VERSION 5.8 ;
BUSBITCHARS "[]" ;
DIVIDERCHAR "/" ;
UNITS
    DATABASE MICRONS 1000 ;
END UNITS

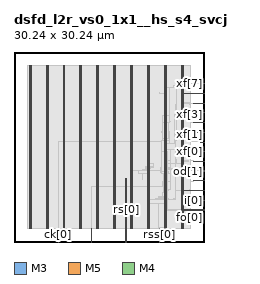
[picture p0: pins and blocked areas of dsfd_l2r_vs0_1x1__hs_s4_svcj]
MACRO dsfd_l2r_vs0_1x1__hs_s4_svcj
  FOREIGN dsfd_l2r_vs0_1x1__hs_s4_svcj 0 0 ;
  CLASS BLOCK ;
  SIZE 30.24 BY 30.24 ;
  PIN ck[0]
    DIRECTION INPUT ;
    USE SIGNAL ;
    PORT
      LAYER M3 ;
        RECT  7.02 0 7.038 0.144 ;
    END
    PORT
      LAYER M3 ;
        RECT  7.02 0.108 7.038 0.52 ;
    END
  END ck[0]
  PIN cks[0]
    DIRECTION INPUT ;
    USE SIGNAL ;
    PORT
      LAYER M5 ;
        RECT  12.384 0 12.408 0.192 ;
    END
    PORT
      LAYER M5 ;
        RECT  12.384 0.144 12.408 2.137 ;
    END
  END cks[0]
  PIN fo[0]
    DIRECTION OUTPUT ;
    USE SIGNAL ;
    PORT
      LAYER M4 ;
        RECT  30.048 5.088 30.24 5.112 ;
    END
    PORT
      LAYER M4 ;
        RECT  27.004 5.088 30.06 5.112 ;
    END
  END fo[0]
  PIN i[0]
    DIRECTION INPUT ;
    USE SIGNAL ;
    PORT
      LAYER M4 ;
        RECT  30.048 6.624 30.24 6.648 ;
    END
    PORT
      LAYER M4 ;
        RECT  28.501 6.624 30.06 6.648 ;
    END
  END i[0]
  PIN i[1]
    DIRECTION INPUT ;
    USE SIGNAL ;
    PORT
      LAYER M4 ;
        RECT  30.048 8.208 30.24 8.232 ;
    END
    PORT
      LAYER M4 ;
        RECT  27.004 8.208 30.06 8.232 ;
    END
  END i[1]
  PIN od[0]
    DIRECTION OUTPUT ;
    USE SIGNAL ;
    PORT
      LAYER M4 ;
        RECT  30.048 9.744 30.24 9.768 ;
    END
    PORT
      LAYER M4 ;
        RECT  28.501 9.744 30.06 9.768 ;
    END
  END od[0]
  PIN od[1]
    DIRECTION OUTPUT ;
    USE SIGNAL ;
    PORT
      LAYER M4 ;
        RECT  30.048 11.28 30.24 11.304 ;
    END
    PORT
      LAYER M4 ;
        RECT  29.653 11.28 30.06 11.304 ;
    END
  END od[1]
  PIN od[2]
    DIRECTION OUTPUT ;
    USE SIGNAL ;
    PORT
      LAYER M4 ;
        RECT  30.048 12.816 30.24 12.84 ;
    END
    PORT
      LAYER M4 ;
        RECT  28.501 12.816 30.06 12.84 ;
    END
  END od[2]
  PIN rs[0]
    DIRECTION INPUT ;
    USE SIGNAL ;
    PORT
      LAYER M3 ;
        RECT  17.82 0 17.838 0.144 ;
    END
    PORT
      LAYER M3 ;
        RECT  17.82 0.108 17.838 10.085 ;
    END
  END rs[0]
  PIN rss[0]
    DIRECTION INPUT ;
    USE SIGNAL ;
    PORT
      LAYER M5 ;
        RECT  23.184 0 23.208 0.192 ;
    END
    PORT
      LAYER M5 ;
        RECT  23.184 0.144 23.208 2.137 ;
    END
  END rss[0]
  PIN xf[0]
    DIRECTION INPUT ;
    USE SIGNAL ;
    PORT
      LAYER M4 ;
        RECT  30.048 14.352 30.24 14.376 ;
    END
    PORT
      LAYER M4 ;
        RECT  29.653 14.352 30.06 14.376 ;
    END
  END xf[0]
  PIN xf[1]
    DIRECTION INPUT ;
    USE SIGNAL ;
    PORT
      LAYER M4 ;
        RECT  30.048 15.888 30.24 15.912 ;
    END
    PORT
      LAYER M4 ;
        RECT  29.653 15.888 30.06 15.912 ;
    END
  END xf[1]
  PIN xf[2]
    DIRECTION INPUT ;
    USE SIGNAL ;
    PORT
      LAYER M4 ;
        RECT  30.048 17.424 30.24 17.448 ;
    END
    PORT
      LAYER M4 ;
        RECT  28.501 17.424 30.06 17.448 ;
    END
  END xf[2]
  PIN xf[3]
    DIRECTION INPUT ;
    USE SIGNAL ;
    PORT
      LAYER M4 ;
        RECT  30.048 19.008 30.24 19.032 ;
    END
    PORT
      LAYER M4 ;
        RECT  28.501 19.008 30.06 19.032 ;
    END
  END xf[3]
  PIN xf[4]
    DIRECTION INPUT ;
    USE SIGNAL ;
    PORT
      LAYER M4 ;
        RECT  30.048 20.544 30.24 20.568 ;
    END
    PORT
      LAYER M4 ;
        RECT  28.501 20.544 30.06 20.568 ;
    END
  END xf[4]
  PIN xf[5]
    DIRECTION INPUT ;
    USE SIGNAL ;
    PORT
      LAYER M4 ;
        RECT  30.048 22.08 30.24 22.104 ;
    END
    PORT
      LAYER M4 ;
        RECT  28.501 22.08 30.06 22.104 ;
    END
  END xf[5]
  PIN xf[6]
    DIRECTION INPUT ;
    USE SIGNAL ;
    PORT
      LAYER M4 ;
        RECT  30.048 23.616 30.24 23.64 ;
    END
    PORT
      LAYER M4 ;
        RECT  27.004 23.616 30.06 23.64 ;
    END
  END xf[6]
  PIN xf[7]
    DIRECTION INPUT ;
    USE SIGNAL ;
    PORT
      LAYER M4 ;
        RECT  30.048 25.152 30.24 25.176 ;
    END
    PORT
      LAYER M4 ;
        RECT  29.653 25.152 30.06 25.176 ;
    END
  END xf[7]
  PIN VDD
    DIRECTION INOUT ;
    USE POWER ;
    PORT
      LAYER M5 ;
        RECT  26.892 2.151 27.012 28.089 ;
        RECT  24.192 2.151 24.312 28.089 ;
        RECT  21.492 2.151 21.612 28.089 ;
        RECT  18.792 2.151 18.912 28.089 ;
        RECT  16.092 2.151 16.212 28.089 ;
        RECT  13.392 2.151 13.512 28.089 ;
        RECT  10.692 2.151 10.812 28.089 ;
        RECT  7.992 2.151 8.112 28.089 ;
        RECT  5.292 2.151 5.412 28.089 ;
        RECT  2.592 2.151 2.712 28.089 ;
    END
  END VDD
  PIN VSS
    DIRECTION INOUT ;
    USE GROUND ;
    PORT
      LAYER M5 ;
        RECT  26.7 2.137 26.82 28.103 ;
        RECT  24 2.137 24.12 28.103 ;
        RECT  21.3 2.137 21.42 28.103 ;
        RECT  18.6 2.137 18.72 28.103 ;
        RECT  15.9 2.137 16.02 28.103 ;
        RECT  13.2 2.137 13.32 28.103 ;
        RECT  10.5 2.137 10.62 28.103 ;
        RECT  7.8 2.137 7.92 28.103 ;
        RECT  5.1 2.137 5.22 28.103 ;
        RECT  2.4 2.137 2.52 28.103 ;
    END
  END VSS
  # OT_OBS_CLOSED layer=M5 d_um=1.536 added=0
  OBS
    LAYER RVTN ;
     RECT  2.16 2.16 28.08 2.295 ;
     RECT  2.16 2.565 28.08 2.835 ;
     RECT  2.16 3.105 28.08 3.375 ;
     RECT  2.16 3.645 28.08 3.915 ;
     RECT  2.16 4.185 28.08 4.455 ;
     RECT  2.16 4.725 28.08 4.995 ;
     RECT  2.16 5.265 28.08 5.535 ;
     RECT  2.16 5.805 28.08 6.075 ;
     RECT  2.16 6.345 28.08 6.615 ;
     RECT  2.16 6.885 28.08 7.155 ;
     RECT  2.16 7.425 28.08 7.695 ;
     RECT  2.16 7.965 28.08 8.235 ;
     RECT  2.16 8.505 28.08 8.775 ;
     RECT  2.16 9.045 28.08 9.315 ;
     RECT  2.16 9.585 28.08 9.855 ;
     RECT  2.16 10.125 28.08 10.395 ;
     RECT  2.16 10.665 28.08 10.935 ;
     RECT  2.16 11.205 28.08 11.475 ;
     RECT  2.16 11.745 28.08 12.015 ;
     RECT  2.16 12.285 28.08 12.555 ;
     RECT  2.16 12.825 28.08 13.095 ;
     RECT  2.16 13.365 28.08 13.635 ;
     RECT  2.16 13.905 28.08 14.175 ;
     RECT  2.16 14.445 28.08 14.715 ;
     RECT  2.16 14.985 28.08 15.255 ;
     RECT  2.16 15.525 28.08 15.795 ;
     RECT  2.16 16.065 28.08 16.335 ;
     RECT  2.16 16.605 28.08 16.875 ;
     RECT  2.16 17.145 28.08 17.415 ;
     RECT  2.16 17.685 28.08 17.955 ;
     RECT  2.16 18.225 28.08 18.495 ;
     RECT  2.16 18.765 28.08 19.035 ;
     RECT  2.16 19.305 28.08 19.575 ;
     RECT  2.16 19.845 28.08 20.115 ;
     RECT  2.16 20.385 28.08 20.655 ;
     RECT  2.16 20.925 28.08 21.195 ;
     RECT  2.16 21.465 28.08 21.735 ;
     RECT  2.16 22.005 28.08 22.275 ;
     RECT  2.16 22.545 28.08 22.815 ;
     RECT  2.16 23.085 28.08 23.355 ;
     RECT  2.16 23.625 28.08 23.895 ;
     RECT  2.16 24.165 28.08 24.435 ;
     RECT  2.16 24.705 28.08 24.975 ;
     RECT  2.16 25.245 28.08 25.515 ;
     RECT  2.16 25.785 28.08 26.055 ;
     RECT  2.16 26.325 28.08 26.595 ;
     RECT  2.16 26.865 28.08 27.135 ;
     RECT  2.16 27.405 28.08 27.675 ;
     RECT  2.16 27.945 28.08 28.08 ;
    LAYER RVTP ;
     RECT  2.16 2.295 28.08 2.565 ;
     RECT  2.16 2.835 28.08 3.105 ;
     RECT  2.16 3.375 28.08 3.645 ;
     RECT  2.16 3.915 28.08 4.185 ;
     RECT  2.16 4.455 28.08 4.725 ;
     RECT  2.16 4.995 28.08 5.265 ;
     RECT  2.16 5.535 28.08 5.805 ;
     RECT  2.16 6.075 28.08 6.345 ;
     RECT  2.16 6.615 28.08 6.885 ;
     RECT  2.16 7.155 28.08 7.425 ;
     RECT  2.16 7.695 28.08 7.965 ;
     RECT  2.16 8.235 28.08 8.505 ;
     RECT  2.16 8.775 28.08 9.045 ;
     RECT  2.16 9.315 28.08 9.585 ;
     RECT  2.16 9.855 28.08 10.125 ;
     RECT  2.16 10.395 28.08 10.665 ;
     RECT  2.16 10.935 28.08 11.205 ;
     RECT  2.16 11.475 28.08 11.745 ;
     RECT  2.16 12.015 28.08 12.285 ;
     RECT  2.16 12.555 28.08 12.825 ;
     RECT  2.16 13.095 28.08 13.365 ;
     RECT  2.16 13.635 28.08 13.905 ;
     RECT  2.16 14.175 28.08 14.445 ;
     RECT  2.16 14.715 28.08 14.985 ;
     RECT  2.16 15.255 28.08 15.525 ;
     RECT  2.16 15.795 28.08 16.065 ;
     RECT  2.16 16.335 28.08 16.605 ;
     RECT  2.16 16.875 28.08 17.145 ;
     RECT  2.16 17.415 28.08 17.685 ;
     RECT  2.16 17.955 28.08 18.225 ;
     RECT  2.16 18.495 28.08 18.765 ;
     RECT  2.16 19.035 28.08 19.305 ;
     RECT  2.16 19.575 28.08 19.845 ;
     RECT  2.16 20.115 28.08 20.385 ;
     RECT  2.16 20.655 28.08 20.925 ;
     RECT  2.16 21.195 28.08 21.465 ;
     RECT  2.16 21.735 28.08 22.005 ;
     RECT  2.16 22.275 28.08 22.545 ;
     RECT  2.16 22.815 28.08 23.085 ;
     RECT  2.16 23.355 28.08 23.625 ;
     RECT  2.16 23.895 28.08 24.165 ;
     RECT  2.16 24.435 28.08 24.705 ;
     RECT  2.16 24.975 28.08 25.245 ;
     RECT  2.16 25.515 28.08 25.785 ;
     RECT  2.16 26.055 28.08 26.325 ;
     RECT  2.16 26.595 28.08 26.865 ;
     RECT  2.16 27.135 28.08 27.405 ;
     RECT  2.16 27.675 28.08 27.945 ;
    LAYER M1 ;
     RECT  2.16 2.151 28.08 28.089 ;
    LAYER M2 ;
     RECT  6.943 0.531 7.043 0.549 ;
     RECT  2.16 2.151 28.08 28.089 ;
     RECT  28.08 6.696 28.535 6.714 ;
     RECT  28.08 9.666 28.535 9.684 ;
     RECT  28.08 12.906 28.535 12.924 ;
     RECT  28.08 17.622 28.535 17.64 ;
     RECT  28.08 18.972 28.535 18.99 ;
     RECT  28.08 20.628 28.535 20.646 ;
     RECT  28.08 22.086 28.535 22.104 ;
     RECT  28.08 11.376 29.687 11.394 ;
     RECT  28.08 14.382 29.687 14.4 ;
     RECT  28.08 16.002 29.687 16.02 ;
     RECT  28.08 25.254 29.687 25.272 ;
    LAYER M3 ;
     RECT  6.948 0.52 7.038 0.554 ;
     RECT  6.948 0.554 6.966 0.557 ;
     RECT  2.415 2.143 2.505 2.413 ;
     RECT  5.115 2.143 5.205 2.413 ;
     RECT  7.815 2.143 7.905 2.413 ;
     RECT  10.515 2.143 10.605 2.413 ;
     RECT  13.215 2.143 13.305 2.413 ;
     RECT  15.915 2.143 16.005 2.413 ;
     RECT  18.615 2.143 18.705 2.413 ;
     RECT  21.315 2.143 21.405 2.413 ;
     RECT  24.015 2.143 24.105 2.413 ;
     RECT  26.715 2.143 26.805 2.413 ;
     RECT  26.715 2.413 26.997 4.891 ;
     RECT  23.04 2.251 23.058 4.955 ;
     RECT  26.715 4.891 27.09 5.035 ;
     RECT  26.064 5.035 27.09 5.117 ;
     RECT  21.315 2.413 21.597 6.115 ;
     RECT  23.004 5.071 23.022 6.115 ;
     RECT  21.315 6.115 23.022 6.151 ;
     RECT  24.015 2.413 24.297 6.151 ;
     RECT  26.715 5.117 26.997 6.691 ;
     RECT  28.512 6.619 28.53 6.719 ;
     RECT  25.704 6.781 25.722 6.808 ;
     RECT  21.315 6.151 24.297 6.809 ;
     RECT  22.464 6.809 24.297 6.845 ;
     RECT  25.416 6.808 25.722 6.845 ;
     RECT  26.715 6.691 27.378 6.845 ;
     RECT  22.932 6.845 24.297 7.079 ;
     RECT  23.076 7.079 24.297 7.223 ;
     RECT  23.688 7.223 24.297 7.889 ;
     RECT  25.704 6.845 25.722 8.131 ;
     RECT  26.715 6.845 26.997 8.131 ;
     RECT  25.704 8.131 26.997 8.231 ;
     RECT  27.936 8.203 27.954 8.303 ;
     RECT  23.76 7.889 24.297 8.311 ;
     RECT  23.76 8.311 24.894 9.689 ;
     RECT  28.512 9.661 28.53 9.773 ;
     RECT  20.412 10.021 20.43 10.975 ;
     RECT  21.315 6.809 21.597 10.975 ;
     RECT  24.015 9.689 24.894 10.975 ;
     RECT  29.664 11.275 29.682 11.399 ;
     RECT  19.8 10.975 21.597 11.453 ;
     RECT  20.412 11.453 21.597 11.507 ;
     RECT  23.4 10.975 24.894 11.515 ;
     RECT  25.704 8.231 25.722 11.515 ;
     RECT  23.4 11.515 25.722 11.669 ;
     RECT  20.88 11.507 21.597 11.677 ;
     RECT  20.88 11.677 21.654 11.705 ;
     RECT  23.4 11.669 24.894 11.785 ;
     RECT  20.952 11.705 21.654 11.821 ;
     RECT  23.364 11.785 24.894 11.837 ;
     RECT  20.952 11.821 22.266 11.975 ;
     RECT  21.315 11.975 22.266 12.515 ;
     RECT  25.704 11.669 25.722 12.523 ;
     RECT  26.715 8.231 26.997 12.865 ;
     RECT  28.512 12.811 28.53 12.929 ;
     RECT  23.94 11.837 24.894 13.019 ;
     RECT  26.715 12.865 27.702 13.019 ;
     RECT  25.704 12.523 25.902 13.027 ;
     RECT  25.668 13.027 25.902 13.055 ;
     RECT  29.664 14.347 29.682 14.405 ;
     RECT  26.715 13.019 26.997 14.611 ;
     RECT  26.64 14.611 26.997 14.711 ;
     RECT  24.015 13.019 24.894 14.791 ;
     RECT  25.668 13.055 25.722 14.791 ;
     RECT  24.015 14.791 25.722 15.719 ;
     RECT  29.664 15.883 29.682 16.025 ;
     RECT  23.04 15.961 23.058 16.061 ;
     RECT  24.015 15.719 24.75 16.105 ;
     RECT  25.596 15.719 25.722 16.141 ;
     RECT  23.616 16.105 24.75 16.157 ;
     RECT  25.596 16.141 25.83 17.149 ;
     RECT  24.015 16.157 24.75 17.467 ;
     RECT  23.436 17.467 24.75 17.609 ;
     RECT  28.512 17.419 28.53 17.645 ;
     RECT  28.512 18.967 28.53 19.037 ;
     RECT  24.015 17.609 24.642 19.075 ;
     RECT  24.015 19.075 24.822 19.133 ;
     RECT  24.015 19.133 24.642 20.191 ;
     RECT  25.596 17.149 25.902 20.309 ;
     RECT  24.015 20.191 24.678 20.477 ;
     RECT  27.792 20.389 27.81 20.539 ;
     RECT  27.792 20.539 28.53 20.579 ;
     RECT  28.512 20.579 28.53 20.651 ;
     RECT  25.74 20.309 25.902 21.929 ;
     RECT  24.015 20.477 24.642 22.045 ;
     RECT  27.864 21.901 27.882 22.075 ;
     RECT  26.715 14.711 26.997 22.081 ;
     RECT  27.864 22.075 28.53 22.081 ;
     RECT  24.015 22.045 24.678 22.109 ;
     RECT  26.715 22.081 28.53 22.115 ;
     RECT  26.715 22.115 27.882 22.199 ;
     RECT  26.715 22.199 27.702 22.235 ;
     RECT  24.015 22.109 24.642 23.549 ;
     RECT  27.936 23.557 27.954 23.645 ;
     RECT  23.112 23.659 23.13 23.729 ;
     RECT  25.884 21.929 25.902 24.523 ;
     RECT  25.416 24.523 25.902 24.899 ;
     RECT  25.416 24.899 25.434 24.935 ;
     RECT  29.664 25.147 29.682 25.277 ;
     RECT  2.415 2.413 2.697 27.827 ;
     RECT  5.115 2.413 5.397 27.827 ;
     RECT  7.815 2.413 8.097 27.827 ;
     RECT  10.515 2.413 10.797 27.827 ;
     RECT  13.215 2.413 13.497 27.827 ;
     RECT  15.915 2.413 16.197 27.827 ;
     RECT  18.615 2.413 18.897 27.827 ;
     RECT  21.315 12.515 21.597 27.827 ;
     RECT  24.015 23.549 24.297 27.827 ;
     RECT  26.715 22.235 26.997 27.827 ;
     RECT  2.415 27.827 2.505 28.097 ;
     RECT  5.115 27.827 5.205 28.097 ;
     RECT  7.815 27.827 7.905 28.097 ;
     RECT  10.515 27.827 10.605 28.097 ;
     RECT  13.215 27.827 13.305 28.097 ;
     RECT  15.915 27.827 16.005 28.097 ;
     RECT  18.615 27.827 18.705 28.097 ;
     RECT  21.315 27.827 21.405 28.097 ;
     RECT  24.015 27.827 24.105 28.097 ;
     RECT  26.715 27.827 26.805 28.097 ;
    LAYER M4 ;
     RECT  2.408 2.148 2.512 28.092 ;
     RECT  2.512 2.418 2.704 27.822 ;
     RECT  5.108 2.148 5.212 28.092 ;
     RECT  5.212 2.418 5.404 27.822 ;
     RECT  6.937 0.528 7.091 0.552 ;
     RECT  7.045 16.032 7.808 16.056 ;
     RECT  7.808 2.148 7.912 28.092 ;
     RECT  7.912 2.418 8.104 27.822 ;
     RECT  8.104 16.032 10.508 16.056 ;
     RECT  10.508 2.148 10.612 28.092 ;
     RECT  10.612 2.418 10.804 27.822 ;
     RECT  12.373 8.784 13.208 8.808 ;
     RECT  10.804 16.032 13.208 16.056 ;
     RECT  13.208 2.148 13.312 28.092 ;
     RECT  13.312 2.418 13.504 27.822 ;
     RECT  13.504 8.784 15.908 8.808 ;
     RECT  13.504 16.032 15.908 16.056 ;
     RECT  15.908 2.148 16.012 28.092 ;
     RECT  16.012 2.418 16.204 27.822 ;
     RECT  16.204 8.784 18.608 8.808 ;
     RECT  16.204 16.032 18.608 16.056 ;
     RECT  18.608 2.148 18.712 28.092 ;
     RECT  18.712 2.418 18.904 27.822 ;
     RECT  18.904 8.784 21.308 8.808 ;
     RECT  18.904 11.424 21.308 11.448 ;
     RECT  18.904 16.032 21.308 16.056 ;
     RECT  21.308 2.148 21.412 28.092 ;
     RECT  21.412 2.418 21.604 27.822 ;
     RECT  21.604 11.424 23.353 11.448 ;
     RECT  23.353 11.424 23.372 11.832 ;
     RECT  21.604 16.032 23.413 16.056 ;
     RECT  23.372 10.992 23.509 11.832 ;
     RECT  21.604 8.784 23.708 8.808 ;
     RECT  23.509 10.992 23.749 12.552 ;
     RECT  23.708 8.784 23.821 9.672 ;
     RECT  21.604 6.816 23.929 6.84 ;
     RECT  23.029 2.256 24.008 2.28 ;
     RECT  23.929 6.672 24.008 6.84 ;
     RECT  23.821 7.92 24.008 9.672 ;
     RECT  23.749 10.704 24.008 12.552 ;
     RECT  23.413 16.032 24.008 16.152 ;
     RECT  23.425 17.472 24.008 17.496 ;
     RECT  23.605 20.112 24.008 20.136 ;
     RECT  23.101 23.664 24.008 23.688 ;
     RECT  24.008 2.148 24.112 28.092 ;
     RECT  24.112 2.418 24.304 27.822 ;
     RECT  24.304 6.672 24.419 6.936 ;
     RECT  24.304 7.92 24.419 8.952 ;
     RECT  24.304 10.272 24.419 11.16 ;
     RECT  24.304 14.4 24.419 14.424 ;
     RECT  24.419 8.256 24.445 8.952 ;
     RECT  24.304 20.112 24.473 20.472 ;
     RECT  24.419 6.816 24.515 6.936 ;
     RECT  24.445 8.256 24.515 8.28 ;
     RECT  24.419 11.136 24.515 11.16 ;
     RECT  24.304 16.416 24.563 17.496 ;
     RECT  24.563 16.416 24.689 16.536 ;
     RECT  24.473 20.448 24.803 20.472 ;
     RECT  24.304 22.08 24.803 22.104 ;
     RECT  24.304 23.664 24.803 24.552 ;
     RECT  24.304 19.104 24.844 19.128 ;
     RECT  24.515 6.816 25.445 6.84 ;
     RECT  24.803 24.528 25.445 24.552 ;
     RECT  24.304 5.088 26.708 5.112 ;
     RECT  24.304 12.528 26.708 12.552 ;
     RECT  26.708 2.148 26.812 28.092 ;
     RECT  26.812 2.418 27.004 27.822 ;
    LAYER M5 ;
     RECT  7.056 0.517 7.08 2.137 ;
     RECT  2.4 2.137 2.52 2.151 ;
     RECT  5.1 2.137 5.22 2.151 ;
     RECT  7.056 2.137 7.92 2.151 ;
     RECT  10.5 2.137 10.62 2.151 ;
     RECT  12.384 2.137 13.32 2.151 ;
     RECT  15.9 2.137 16.02 2.151 ;
     RECT  18.6 2.137 18.72 2.151 ;
     RECT  21.3 2.137 21.42 2.151 ;
     RECT  23.184 2.137 24.12 2.151 ;
     RECT  26.7 2.137 26.82 2.151 ;
     RECT  23.184 2.151 24.312 2.291 ;
     RECT  24 2.291 24.312 5.077 ;
     RECT  24 5.077 24.408 6.901 ;
     RECT  12.384 2.151 13.512 8.819 ;
     RECT  24 6.901 24.504 9.637 ;
     RECT  23.76 9.637 24.504 10.981 ;
     RECT  23.424 10.981 24.504 11.171 ;
     RECT  23.424 11.171 24.408 14.435 ;
     RECT  7.056 2.151 8.112 16.067 ;
     RECT  23.424 14.435 24.312 16.163 ;
     RECT  23.616 16.163 24.312 16.405 ;
     RECT  23.616 16.405 24.6 19.093 ;
     RECT  23.616 19.093 24.792 20.147 ;
     RECT  24 20.147 24.792 24.563 ;
     RECT  2.4 2.151 2.712 28.089 ;
     RECT  5.1 2.151 5.412 28.089 ;
     RECT  7.8 16.067 8.112 28.089 ;
     RECT  10.5 2.151 10.812 28.089 ;
     RECT  13.2 8.819 13.512 28.089 ;
     RECT  15.9 2.151 16.212 28.089 ;
     RECT  18.6 2.151 18.912 28.089 ;
     RECT  21.3 2.151 21.612 28.089 ;
     RECT  24 24.563 24.312 28.089 ;
     RECT  26.7 2.151 27.012 28.089 ;
     RECT  2.4 28.089 2.52 28.103 ;
     RECT  5.1 28.089 5.22 28.103 ;
     RECT  7.8 28.089 7.92 28.103 ;
     RECT  10.5 28.089 10.62 28.103 ;
     RECT  13.2 28.089 13.32 28.103 ;
     RECT  15.9 28.089 16.02 28.103 ;
     RECT  18.6 28.089 18.72 28.103 ;
     RECT  21.3 28.089 21.42 28.103 ;
     RECT  24 28.089 24.12 28.103 ;
     RECT  26.7 28.089 26.82 28.103 ;
  END
END dsfd_l2r_vs0_1x1__hs_s4_svcj
END LIBRARY
